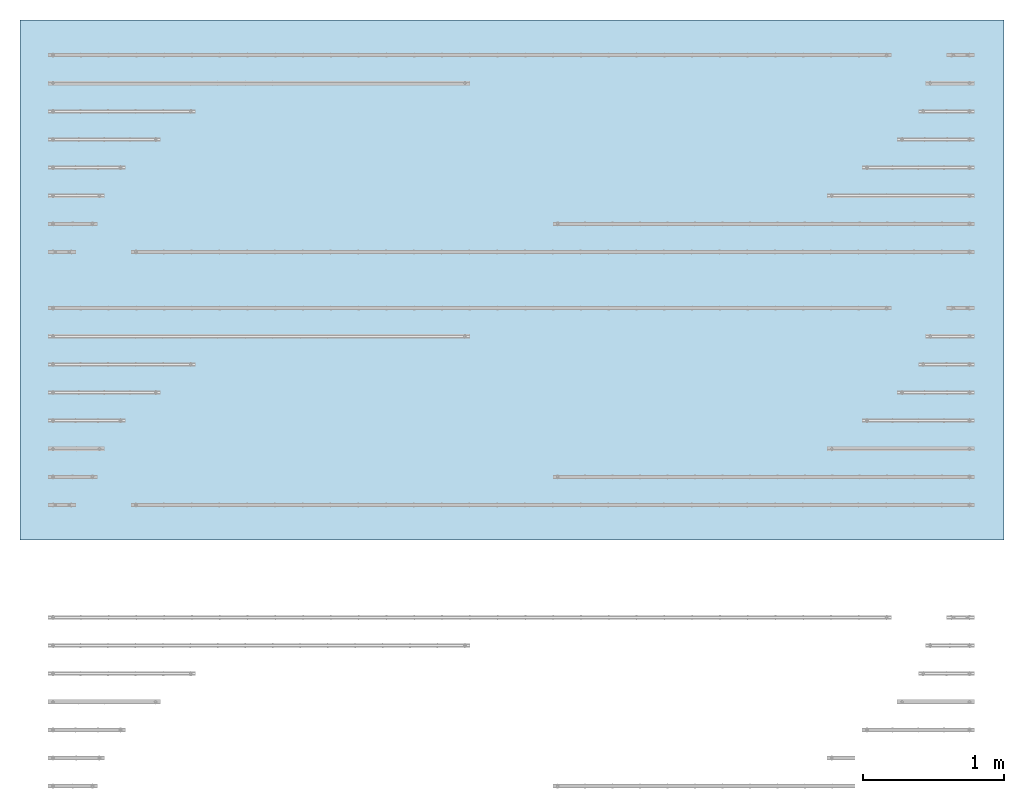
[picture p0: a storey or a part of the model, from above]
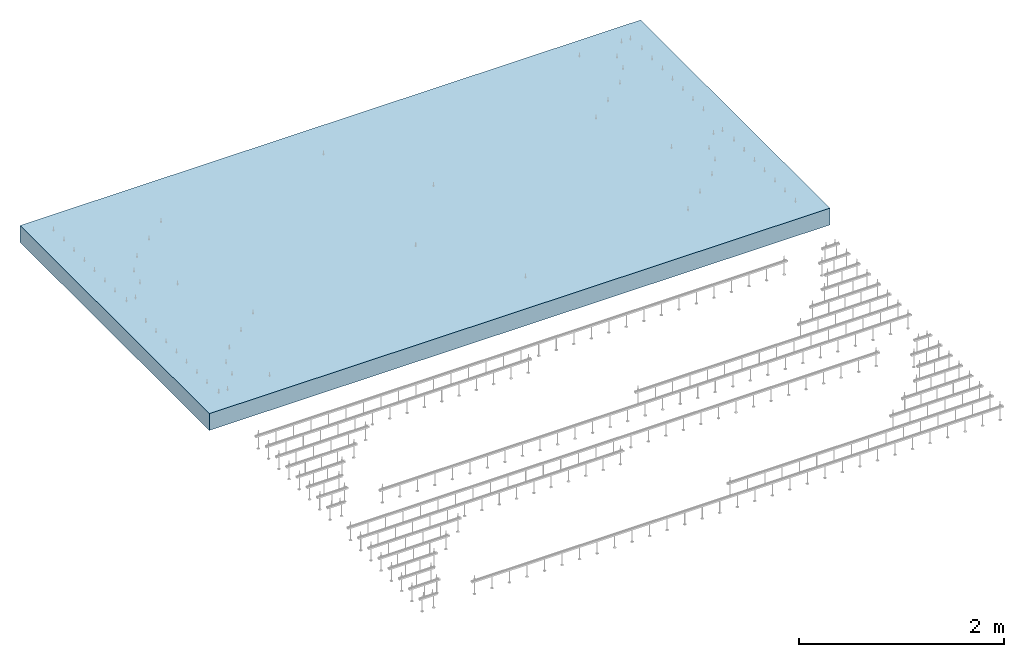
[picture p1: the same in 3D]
Properties of the parts of a building model (IFC2X3)

# File
Description: ViewDefinition [CoordinationView_V2.0]
File name: Projektnummer
Time: 2018-11-02T15:20:55
Written by: The EXPRESS Data Manager Version 5.02.0100.07 : 28 Aug 2013
Made in: 20140606_1530(x64) - Exporter 15.7.0.0 - Alternate UI 15.7.0.0
Comment: STEP Physical File produced by: The EXPRESS Data Manager Version 5.02.0100.07 : 28 Aug 2013 * Module: EDMstepFileFactory/EDMstandAlone * Creation date: Fri Nov 02 15:20:55 2018 * Host: JORNBBLN-012 * Database: C:\Users\DENNIS~1.NEU\AppData\Local\Temp\{C2517105-60E5-48DE-9BF2-83D51E9DFE25}\ifc * Database version: 5507 * Database creation date: Fri Nov 02 15:20:52 2018 * Schema: IFC2X3 * Model: DataRepository.ifc * Model creation date: Fri Nov 02 15:20:52 2018 * Header model: DataRepository.ifc_HeaderModel * Header model creation date: Fri Nov 02 15:20:52 2018 * EDMuser: sdai-user * EDMgroup: sdai-group * License ID and type: 5605 : Permanent license. Expiry date: * EDMstepFileFactory options: 020000

# IfcProject, Projektnummer
LongName: Projektname; Phase: Projektstatus

# IfcSite, Default
RefLatitude: 52, 30, 59, 759999; RefLongitude: 13, 23, 59, 999999; RefElevation: 0 m
Sonstige - Kategorie: Projektinformationen; Kundenname: Bauherr; Projektadresse: Projektadresse; Projektausgabedatum: Projekt Datum; Projektname: Projektname; Projektnummer: Projektnummer; Projektstatus: Projektstatus; Verfasser eMail: E-Mail; Verfasser Firma 1: Firma 1; Verfasser Firma 2: Firma 2; Verfasser PLZ Ort: PLZ Ort; Verfasser Strasse: Strasse; Verfasser Telefax: Telefax; Verfasser Telefon: Telefon

# IfcBuilding
Pset_BuildingCommon - NumberOfStoreys: 1
Sonstige - Kategorie: Projektinformationen; Kundenname: Bauherr; Projektadresse: Projektadresse; Projektausgabedatum: Projekt Datum; Projektname: Projektname; Projektnummer: Projektnummer; Projektstatus: Projektstatus; Verfasser eMail: E-Mail; Verfasser Firma 1: Firma 1; Verfasser Firma 2: Firma 2; Verfasser PLZ Ort: PLZ Ort; Verfasser Strasse: Strasse; Verfasser Telefax: Telefax; Verfasser Telefon: Telefon

# IfcBuildingStorey, Ebene 0
LongName: Ebene 0; Elevation: 0 m
Sonstige(Type) - Kategorie: Ebenen; Familienname: Ebene
ID-Daten(Type) - Typname: Ebene
Grafiken(Type) - Farbe: 16711680; Linienmuster: Verdeckt; Linienstärke: 1; Symbol: Beschriftung Ebene: Beschriftung Ebene; Symbol bei Ende 1 Standard: no; Symbol bei Ende 2 Standard: yes
Abhängigkeiten(Type) - Basishöhe: Projekt-Basispunkt
Abhängigkeiten - Ansicht: 0 m
Abmessungen - Höhe für Berechnung: 0 m
ID-Daten - Tragwerk: no; Gebäudegeschoss: yes; Name: Ebene 0
Sonstige - Familie: Ebene: Ebene; Familie und Typ: Ebene: Ebene; Kategorie: Ebenen; Typ: Ebene: Ebene; Typ-ID: Ebene: Ebene

# IfcFastener: JXA(-PC) L=1050 mm (8)
In: Ebene 0
Type - Material: Steel
Type - Abhängigkeiten(Type) - Vorgabe-Ansicht: 0 m; length: 1.05 m
Type - Allgemein(Type) - min number anchor: 2; tk: 0.002 m
Type - Daten(Type) - min_number_of_T_bolts: 2
Type - ID-Daten(Type) - Beschreibung: Together with the JORDAHL® toothed T-bolts and JORDAHL® accessories, the hot-rolled toothed JORDAHL® anchor channels provide a secure, form-fitting connection along the longitudinal axis of the channel. They can absorb static and dynamic tensile loads, shear loads and longitudinal tension.; Hersteller: JORDAHL®; LOD: 300; Modell: JXA(-PC) W; Typname: JXA(-PC) L=1050 mm; URL: http://www.jordahl-group.com/en/354/products/fastening-technology/toothed-channels-jxa/; Version: 2017-1
Type - Sichtbarkeit(Type) - proof 29-20: W 29-20 JXA JORDAHL®; proof 38-23: W 38-23 JXA JORDAHL®; proof 53-34: W 53-34 JXA JORDAHL®; proof 64-44: W 64-44 JXA JORDAHL®
Type - Sonstige(Type) - Kategorie: Anschluss; Familienname: JXA(-PC) JORDAHL® toothed channels
Type - Text(Type) - delivery date: XX.XX.XXXX; OmniClass Code: 23-13 23 11 11
Pset_ManufacturerTypeInformation - Manufacturer: JORDAHL®
JORDAHL-Liste - JXA-PC: yes; larger T-Bolt size: no; material hot-dip Galvanised steel: no; material stainless steel: yes; b: 0.029 m; b1: 0.013 m; b2: 0.021 m; channel profil: W 29-20 JXA JORDAHL®; delivery date: XX.XX.XXXX; Familie und Typ: JXA(-PC) JORDAHL® toothed channels: JXA(-PC) L=1050 mm; Hersteller: JORDAHL®; length: 1.05 m; Modell: JXA(-PC) W; number of T Bolts: 2; T Bolt length: 0.06 m; T Bolt type: JXD M10
Abhängigkeiten - JXA-PC: yes; larger T-Bolt size: no; channel profil: W 29-20 JXA JORDAHL®; Ebene: Ebene: Ebene 0; Erhebung: 0 m; Warning Overconstraint: no; Assessment Z-21.4-1690: http://downloads.jordahl-group.com/files/approvals/Z-21.4-1690_JORDAHL_anchor_channel_JXA.pdf; Basisbauteil: Ebene : Ebene 0; Website: http://www.jordahl-group.com/en/354/products/fastening-technology/toothed-channels-jxa/
Abmessungen - Fläche: 0.113151 m2; Volumen: 0.000350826 m3
Allgemein - calculate H: 0.146 m; calculate max spacing anchor: 0.2 m; calculate ØbA: 0.006 m; calculate ØD: 0.0145 m; calculate Øk1: 0.018 m; edge distance anchor: 0.035 m; number anchor: 6; ØbA: 0.012 m; ØD: 0.029 m; Øk1: 0.036 m; tD: 0.0025 m
Daten - calculated_number_of_T_bolts: 2; nut_1: no; nut_pair: yes; b1: 0.013 m; b2: 0.021 m; edge distance of the first T Bolt: 0.035 m; k: 0.007 m; l: 0.06 m; max_spacing_length: 0.98 m; max clamping length: 0.04 m; min_spacing_length: 0.05 m; Ød_SharedParameter: 0.01 m; T Bolt group spacing: 0.49 m; T Bolt min length: 0.03 m
ID-Daten - tender text: gezahnte JORDAHL® Ankerschiene JXA ... / ... oder gleichwertig zum Einbetonieren, Material:feuerverzinkt (fv) oder Edelstahl 1.4401; 1.4571; 1.4404 (A4) mit Vollschaumfüllung, nach allgemeiner bauaufsichtlicher Zulassung des DIBt (Zul.Nr. Z-21.4-1690), versehen mit dem RAL Gütezeichen RAL-GZ 658/1 der Gütegemeinschaft Verankerungs- und Bewehrungstechnik e.V. Einzellänge ........ mm, Belastung Fy/Fz und Fx in Schienenrichtung bis ........kN/Befestigungspunkt, bis ......kN nicht ruhende Beanspruchung zulässig, für die justierbare Befestigung von Anschluss- konstruktionen, liefern und entsprechend der Einbau- anleitung des Herstellers an der Schalung befestigen.
Konstruktion - number of T Bolts: 2; min T Bolt edge distance: 0.035 m; T Bolt diameter: 0.01 m; T Bolt length: 0.06 m; T Bolt spacing: 0.98 m; T Bolt type: JXD M10; thickness of attaching part: 0.01 m
Materialien und Oberflächen - material hot-dip Galvanised steel: no; material stainless steel: yes
Modelleigenschaften - b: 0.029 m; d: 0.014 m; f: 0.005 m; f1: 0.003 m; h: 0.02 m; t1: 0.0025 m
Phasen - Phase erstellt: Phase 1
Sonstige - Bauteillistenebene: Ebene: Ebene 0; Kategorie: Anschluss; Familie: JXA(-PC) JORDAHL® toothed channels: JXA(-PC) L=1050 mm; Familie und Typ: JXA(-PC) JORDAHL® toothed channels: JXA(-PC) L=1050 mm; m_nut: 0.008 m; r_Ød: 0.005 m; s_nut: 0.017 m; s_washer: 0.002 m; Typ: JXA(-PC) JORDAHL® toothed channels: JXA(-PC) L=1050 mm; Typ-ID: JXA(-PC) JORDAHL® toothed channels: JXA(-PC) L=1050 mm
Tragwerk - Bewehrungsüberdeckung: Bewehrungsüberdeckung - Einstellungen: Bewehrungsabdeckung 1
Name (JXA(-PC) JORDAHL® toothed channels:JXA(-PC) L=1050 mm:...) | d_washer (m)
383424 | 0.011
385325 | Sonstige - D_washer: 0.02 m
386284 | Sonstige - D_washer: 0.02 m
386292 | Sonstige - D_washer: 0.02 m
417945 | 0.011
417953 | 0.011
417961 | 0.011
417968 | 0.011

# IfcFastener: JXA(-PC) L=200 mm (8)
In: Ebene 0
Type - Material: Steel
Type - Abhängigkeiten(Type) - length: 0.2 m; Vorgabe-Ansicht: 0 m
Type - Allgemein(Type) - min number anchor: 2; tk: 0.002 m
Type - Daten(Type) - min_number_of_T_bolts: 2
Type - ID-Daten(Type) - Beschreibung: Together with the JORDAHL® toothed T-bolts and JORDAHL® accessories, the hot-rolled toothed JORDAHL® anchor channels provide a secure, form-fitting connection along the longitudinal axis of the channel. They can absorb static and dynamic tensile loads, shear loads and longitudinal tension.; Hersteller: JORDAHL®; LOD: 300; Modell: JXA(-PC) W; Typname: JXA(-PC) L=200 mm; URL: http://www.jordahl-group.com/en/354/products/fastening-technology/toothed-channels-jxa/; Version: 2017-1
Type - Sichtbarkeit(Type) - proof 29-20: W 29-20 JXA JORDAHL®; proof 38-23: W 38-23 JXA JORDAHL®; proof 53-34: W 53-34 JXA JORDAHL®; proof 64-44: W 64-44 JXA JORDAHL®
Type - Sonstige(Type) - Kategorie: Anschluss; Familienname: JXA(-PC) JORDAHL® toothed channels
Type - Text(Type) - delivery date: XX.XX.XXXX; OmniClass Code: 23-13 23 11 11
Pset_ManufacturerTypeInformation - Manufacturer: JORDAHL®
JORDAHL-Liste - b: 0.029 m; b1: 0.013 m; b2: 0.021 m; channel profil: W 29-20 JXA JORDAHL®; delivery date: XX.XX.XXXX; Familie und Typ: JXA(-PC) JORDAHL® toothed channels: JXA(-PC) L=200 mm; Hersteller: JORDAHL®; JXA-PC: yes; larger T-Bolt size: no; length: 0.2 m; material hot-dip Galvanised steel: no; material stainless steel: yes; Modell: JXA(-PC) W; number of T Bolts: 2; T Bolt length: 0.06 m; T Bolt type: JXD M10
Abhängigkeiten - JXA-PC: yes; larger T-Bolt size: no; Assessment Z-21.4-1690: http://downloads.jordahl-group.com/files/approvals/Z-21.4-1690_JORDAHL_anchor_channel_JXA.pdf; Basisbauteil: Ebene : Ebene 0; channel profil: W 29-20 JXA JORDAHL®; Ebene: Ebene: Ebene 0; Erhebung: 0 m; Warning Overconstraint: no; Website: http://www.jordahl-group.com/en/354/products/fastening-technology/toothed-channels-jxa/
Abmessungen - Fläche: 0.0309744 m2; Volumen: 0.000105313 m3
Allgemein - calculate H: 0.146 m; calculate max spacing anchor: 0.2 m; calculate ØbA: 0.006 m; calculate ØD: 0.0145 m; calculate Øk1: 0.018 m; edge distance anchor: 0.035 m; number anchor: 2; ØbA: 0.012 m; ØD: 0.029 m; Øk1: 0.036 m; tD: 0.0025 m
Daten - b1: 0.013 m; b2: 0.021 m; calculated_number_of_T_bolts: 2; edge distance of the first T Bolt: 0.05 m; k: 0.007 m; l: 0.06 m; max_spacing_length: 0.13 m; max clamping length: 0.04 m; min_spacing_length: 0.05 m; nut_1: no; nut_pair: yes; Ød_SharedParameter: 0.01 m; T Bolt group spacing: 0.05 m; T Bolt min length: 0.03 m
ID-Daten - tender text: gezahnte JORDAHL® Ankerschiene JXA ... / ... oder gleichwertig zum Einbetonieren, Material:feuerverzinkt (fv) oder Edelstahl 1.4401; 1.4571; 1.4404 (A4) mit Vollschaumfüllung, nach allgemeiner bauaufsichtlicher Zulassung des DIBt (Zul.Nr. Z-21.4-1690), versehen mit dem RAL Gütezeichen RAL-GZ 658/1 der Gütegemeinschaft Verankerungs- und Bewehrungstechnik e.V. Einzellänge ........ mm, Belastung Fy/Fz und Fx in Schienenrichtung bis ........kN/Befestigungspunkt, bis ......kN nicht ruhende Beanspruchung zulässig, für die justierbare Befestigung von Anschluss- konstruktionen, liefern und entsprechend der Einbau- anleitung des Herstellers an der Schalung befestigen.
Konstruktion - min T Bolt edge distance: 0.035 m; number of T Bolts: 2; T Bolt diameter: 0.01 m; T Bolt length: 0.06 m; T Bolt spacing: 0.1 m; T Bolt type: JXD M10; thickness of attaching part: 0.01 m
Materialien und Oberflächen - material hot-dip Galvanised steel: no; material stainless steel: yes
Modelleigenschaften - b: 0.029 m; d: 0.014 m; f: 0.005 m; f1: 0.003 m; h: 0.02 m; t1: 0.0025 m
Phasen - Phase erstellt: Phase 1
Sonstige - Bauteillistenebene: Ebene: Ebene 0; Familie: JXA(-PC) JORDAHL® toothed channels: JXA(-PC) L=200 mm; Familie und Typ: JXA(-PC) JORDAHL® toothed channels: JXA(-PC) L=200 mm; Kategorie: Anschluss; m_nut: 0.008 m; r_Ød: 0.005 m; s_nut: 0.017 m; s_washer: 0.002 m; Typ: JXA(-PC) JORDAHL® toothed channels: JXA(-PC) L=200 mm; Typ-ID: JXA(-PC) JORDAHL® toothed channels: JXA(-PC) L=200 mm
Tragwerk - Bewehrungsüberdeckung: Bewehrungsüberdeckung - Einstellungen: Bewehrungsabdeckung 1
Name (JXA(-PC) JORDAHL® toothed channels:JXA(-PC) L=200 mm:...) | D_washer (m)
382032 | Sonstige - d_washer: 0.011 m
385320 | 0.02
386279 | Sonstige - d_washer: 0.011 m
407395 | 0.02
417940 | 0.02
417948 | 0.02
417956 | 0.02
417971 | Sonstige - d_washer: 0.011 m

# IfcFastener: JXA(-PC) L=3000 mm (8)
In: Ebene 0
Type - Material: Steel
Type - Abhängigkeiten(Type) - Vorgabe-Ansicht: 0 m; length: 3 m
Type - Allgemein(Type) - min number anchor: 2; tk: 0.002 m
Type - Daten(Type) - min_number_of_T_bolts: 2
Type - ID-Daten(Type) - Beschreibung: Together with the JORDAHL® toothed T-bolts and JORDAHL® accessories, the hot-rolled toothed JORDAHL® anchor channels provide a secure, form-fitting connection along the longitudinal axis of the channel. They can absorb static and dynamic tensile loads, shear loads and longitudinal tension.; Hersteller: JORDAHL®; LOD: 300; Modell: JXA(-PC) W; Typname: JXA(-PC) L=3000 mm; URL: http://www.jordahl-group.com/en/354/products/fastening-technology/toothed-channels-jxa/; Version: 2017-1
Type - Sichtbarkeit(Type) - proof 29-20: W 29-20 JXA JORDAHL®; proof 38-23: W 38-23 JXA JORDAHL®; proof 53-34: W 53-34 JXA JORDAHL®; proof 64-44: W 64-44 JXA JORDAHL®
Type - Sonstige(Type) - Kategorie: Anschluss; Familienname: JXA(-PC) JORDAHL® toothed channels
Type - Text(Type) - delivery date: XX.XX.XXXX; OmniClass Code: 23-13 23 11 11
Pset_ManufacturerTypeInformation - Manufacturer: JORDAHL®
JORDAHL-Liste - JXA-PC: yes; larger T-Bolt size: no; material hot-dip Galvanised steel: no; material stainless steel: yes; b: 0.029 m; b1: 0.013 m; b2: 0.021 m; channel profil: W 29-20 JXA JORDAHL®; delivery date: XX.XX.XXXX; Familie und Typ: JXA(-PC) JORDAHL® toothed channels: JXA(-PC) L=3000 mm; Hersteller: JORDAHL®; length: 3 m; Modell: JXA(-PC) W; number of T Bolts: 2; T Bolt length: 0.06 m; T Bolt type: JXD M10
Abhängigkeiten - JXA-PC: yes; larger T-Bolt size: no; channel profil: W 29-20 JXA JORDAHL®; Ebene: Ebene: Ebene 0; Erhebung: 0 m; Warning Overconstraint: no; Assessment Z-21.4-1690: http://downloads.jordahl-group.com/files/approvals/Z-21.4-1690_JORDAHL_anchor_channel_JXA.pdf; Basisbauteil: Ebene : Ebene 0; Website: http://www.jordahl-group.com/en/354/products/fastening-technology/toothed-channels-jxa/
Abmessungen - Fläche: 0.305203 m2; Volumen: 0.00093136 m3
Allgemein - calculate H: 0.146 m; calculate max spacing anchor: 0.2 m; calculate ØbA: 0.006 m; calculate ØD: 0.0145 m; calculate Øk1: 0.018 m; edge distance anchor: 0.035 m; number anchor: 16; ØbA: 0.012 m; ØD: 0.029 m; Øk1: 0.036 m; tD: 0.0025 m
Daten - calculated_number_of_T_bolts: 2; nut_1: no; nut_pair: yes; b1: 0.013 m; b2: 0.021 m; edge distance of the first T Bolt: 0.035 m; k: 0.007 m; l: 0.06 m; max_spacing_length: 2.93 m; max clamping length: 0.04 m; min_spacing_length: 0.05 m; Ød_SharedParameter: 0.01 m; T Bolt group spacing: 1.465 m; T Bolt min length: 0.03 m
ID-Daten - tender text: gezahnte JORDAHL® Ankerschiene JXA ... / ... oder gleichwertig zum Einbetonieren, Material:feuerverzinkt (fv) oder Edelstahl 1.4401; 1.4571; 1.4404 (A4) mit Vollschaumfüllung, nach allgemeiner bauaufsichtlicher Zulassung des DIBt (Zul.Nr. Z-21.4-1690), versehen mit dem RAL Gütezeichen RAL-GZ 658/1 der Gütegemeinschaft Verankerungs- und Bewehrungstechnik e.V. Einzellänge ........ mm, Belastung Fy/Fz und Fx in Schienenrichtung bis ........kN/Befestigungspunkt, bis ......kN nicht ruhende Beanspruchung zulässig, für die justierbare Befestigung von Anschluss- konstruktionen, liefern und entsprechend der Einbau- anleitung des Herstellers an der Schalung befestigen.
Konstruktion - number of T Bolts: 2; min T Bolt edge distance: 0.035 m; T Bolt diameter: 0.01 m; T Bolt length: 0.06 m; T Bolt spacing: 2.93 m; T Bolt type: JXD M10; thickness of attaching part: 0.01 m
Materialien und Oberflächen - material hot-dip Galvanised steel: no; material stainless steel: yes
Modelleigenschaften - b: 0.029 m; d: 0.014 m; f: 0.005 m; f1: 0.003 m; h: 0.02 m; t1: 0.0025 m
Phasen - Phase erstellt: Phase 1
Sonstige - Bauteillistenebene: Ebene: Ebene 0; Kategorie: Anschluss; Familie: JXA(-PC) JORDAHL® toothed channels: JXA(-PC) L=3000 mm; Familie und Typ: JXA(-PC) JORDAHL® toothed channels: JXA(-PC) L=3000 mm; m_nut: 0.008 m; r_Ød: 0.005 m; s_nut: 0.017 m; s_washer: 0.002 m; Typ: JXA(-PC) JORDAHL® toothed channels: JXA(-PC) L=3000 mm; Typ-ID: JXA(-PC) JORDAHL® toothed channels: JXA(-PC) L=3000 mm
Tragwerk - Bewehrungsüberdeckung: Bewehrungsüberdeckung - Einstellungen: Bewehrungsabdeckung 1
Name (JXA(-PC) JORDAHL® toothed channels:JXA(-PC) L=3000 mm:...) | d_washer (m)
383608 | Sonstige - D_washer: 0.02 m
385326 | 0.011
386285 | Sonstige - D_washer: 0.02 m
386293 | 0.011
417946 | Sonstige - D_washer: 0.02 m
417954 | 0.011
417962 | 0.011
417969 | 0.011

# IfcFastener: JXA(-PC) L=350 mm (8)
In: Ebene 0
Type - Material: Steel
Type - Abhängigkeiten(Type) - Vorgabe-Ansicht: 0 m; length: 0.35 m
Type - Allgemein(Type) - min number anchor: 2; tk: 0.002 m
Type - Daten(Type) - min_number_of_T_bolts: 2
Type - ID-Daten(Type) - Beschreibung: Together with the JORDAHL® toothed T-bolts and JORDAHL® accessories, the hot-rolled toothed JORDAHL® anchor channels provide a secure, form-fitting connection along the longitudinal axis of the channel. They can absorb static and dynamic tensile loads, shear loads and longitudinal tension.; Hersteller: JORDAHL®; LOD: 300; Modell: JXA(-PC) W; Typname: JXA(-PC) L=350 mm; URL: http://www.jordahl-group.com/en/354/products/fastening-technology/toothed-channels-jxa/; Version: 2017-1
Type - Sichtbarkeit(Type) - proof 29-20: W 29-20 JXA JORDAHL®; proof 38-23: W 38-23 JXA JORDAHL®; proof 53-34: W 53-34 JXA JORDAHL®; proof 64-44: W 64-44 JXA JORDAHL®
Type - Sonstige(Type) - Kategorie: Anschluss; Familienname: JXA(-PC) JORDAHL® toothed channels
Type - Text(Type) - delivery date: XX.XX.XXXX; OmniClass Code: 23-13 23 11 11
Pset_ManufacturerTypeInformation - Manufacturer: JORDAHL®
JORDAHL-Liste - JXA-PC: yes; larger T-Bolt size: no; material hot-dip Galvanised steel: no; material stainless steel: yes; b: 0.029 m; b1: 0.013 m; b2: 0.021 m; channel profil: W 29-20 JXA JORDAHL®; delivery date: XX.XX.XXXX; Familie und Typ: JXA(-PC) JORDAHL® toothed channels: JXA(-PC) L=350 mm; Hersteller: JORDAHL®; length: 0.35 m; Modell: JXA(-PC) W; number of T Bolts: 2; T Bolt length: 0.06 m; T Bolt type: JXD M10
Abhängigkeiten - JXA-PC: yes; larger T-Bolt size: no; channel profil: W 29-20 JXA JORDAHL®; Ebene: Ebene: Ebene 0; Erhebung: 0 m; Warning Overconstraint: no; Assessment Z-21.4-1690: http://downloads.jordahl-group.com/files/approvals/Z-21.4-1690_JORDAHL_anchor_channel_JXA.pdf; Basisbauteil: Ebene : Ebene 0; Website: http://www.jordahl-group.com/en/354/products/fastening-technology/toothed-channels-jxa/
Abmessungen - Fläche: 0.0467372 m2; Volumen: 0.000154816 m3
Allgemein - calculate H: 0.146 m; calculate max spacing anchor: 0.2 m; calculate ØbA: 0.006 m; calculate ØD: 0.0145 m; calculate Øk1: 0.018 m; edge distance anchor: 0.035 m; number anchor: 3; ØbA: 0.012 m; ØD: 0.029 m; Øk1: 0.036 m; tD: 0.0025 m
Daten - calculated_number_of_T_bolts: 2; nut_1: no; nut_pair: yes; b1: 0.013 m; b2: 0.021 m; edge distance of the first T Bolt: 0.035 m; k: 0.007 m; l: 0.06 m; max_spacing_length: 0.28 m; max clamping length: 0.04 m; min_spacing_length: 0.05 m; Ød_SharedParameter: 0.01 m; T Bolt group spacing: 0.14 m; T Bolt min length: 0.03 m
ID-Daten - tender text: gezahnte JORDAHL® Ankerschiene JXA ... / ... oder gleichwertig zum Einbetonieren, Material:feuerverzinkt (fv) oder Edelstahl 1.4401; 1.4571; 1.4404 (A4) mit Vollschaumfüllung, nach allgemeiner bauaufsichtlicher Zulassung des DIBt (Zul.Nr. Z-21.4-1690), versehen mit dem RAL Gütezeichen RAL-GZ 658/1 der Gütegemeinschaft Verankerungs- und Bewehrungstechnik e.V. Einzellänge ........ mm, Belastung Fy/Fz und Fx in Schienenrichtung bis ........kN/Befestigungspunkt, bis ......kN nicht ruhende Beanspruchung zulässig, für die justierbare Befestigung von Anschluss- konstruktionen, liefern und entsprechend der Einbau- anleitung des Herstellers an der Schalung befestigen.
Konstruktion - number of T Bolts: 2; min T Bolt edge distance: 0.035 m; T Bolt diameter: 0.01 m; T Bolt length: 0.06 m; T Bolt spacing: 0.28 m; T Bolt type: JXD M10; thickness of attaching part: 0.01 m
Materialien und Oberflächen - material hot-dip Galvanised steel: no; material stainless steel: yes
Modelleigenschaften - b: 0.029 m; d: 0.014 m; f: 0.005 m; f1: 0.003 m; h: 0.02 m; t1: 0.0025 m
Phasen - Phase erstellt: Phase 1
Sonstige - Bauteillistenebene: Ebene: Ebene 0; Kategorie: Anschluss; Familie: JXA(-PC) JORDAHL® toothed channels: JXA(-PC) L=350 mm; Familie und Typ: JXA(-PC) JORDAHL® toothed channels: JXA(-PC) L=350 mm; m_nut: 0.008 m; r_Ød: 0.005 m; s_nut: 0.017 m; s_washer: 0.002 m; Typ: JXA(-PC) JORDAHL® toothed channels: JXA(-PC) L=350 mm; Typ-ID: JXA(-PC) JORDAHL® toothed channels: JXA(-PC) L=350 mm
Tragwerk - Bewehrungsüberdeckung: Bewehrungsüberdeckung - Einstellungen: Bewehrungsabdeckung 1
Name (JXA(-PC) JORDAHL® toothed channels:JXA(-PC) L=350 mm:...) | D_washer (m)
382279 | Sonstige - d_washer: 0.011 m
385321 | Sonstige - d_washer: 0.011 m
386280 | 0.02
386288 | 0.02
417941 | 0.02
417949 | 0.02
417957 | 0.02
417964 | Sonstige - d_washer: 0.011 m

# IfcFastener: JXA(-PC) L=400 mm (8)
In: Ebene 0
Type - Material: Steel
Type - Abhängigkeiten(Type) - Vorgabe-Ansicht: 0 m; length: 0.4 m
Type - Allgemein(Type) - min number anchor: 2; tk: 0.002 m
Type - Daten(Type) - min_number_of_T_bolts: 2
Type - ID-Daten(Type) - Beschreibung: Together with the JORDAHL® toothed T-bolts and JORDAHL® accessories, the hot-rolled toothed JORDAHL® anchor channels provide a secure, form-fitting connection along the longitudinal axis of the channel. They can absorb static and dynamic tensile loads, shear loads and longitudinal tension.; Hersteller: JORDAHL®; LOD: 300; Modell: JXA(-PC) W; Typname: JXA(-PC) L=400 mm; URL: http://www.jordahl-group.com/en/354/products/fastening-technology/toothed-channels-jxa/; Version: 2017-1
Type - Sichtbarkeit(Type) - proof 29-20: W 29-20 JXA JORDAHL®; proof 38-23: W 38-23 JXA JORDAHL®; proof 53-34: W 53-34 JXA JORDAHL®; proof 64-44: W 64-44 JXA JORDAHL®
Type - Sonstige(Type) - Kategorie: Anschluss; Familienname: JXA(-PC) JORDAHL® toothed channels
Type - Text(Type) - delivery date: XX.XX.XXXX; OmniClass Code: 23-13 23 11 11
Pset_ManufacturerTypeInformation - Manufacturer: JORDAHL®
JORDAHL-Liste - JXA-PC: yes; larger T-Bolt size: no; material hot-dip Galvanised steel: no; material stainless steel: yes; b: 0.029 m; b1: 0.013 m; b2: 0.021 m; channel profil: W 29-20 JXA JORDAHL®; delivery date: XX.XX.XXXX; Familie und Typ: JXA(-PC) JORDAHL® toothed channels: JXA(-PC) L=400 mm; Hersteller: JORDAHL®; length: 0.4 m; Modell: JXA(-PC) W; number of T Bolts: 2; T Bolt length: 0.06 m; T Bolt type: JXD M10
Abhängigkeiten - JXA-PC: yes; larger T-Bolt size: no; channel profil: W 29-20 JXA JORDAHL®; Ebene: Ebene: Ebene 0; Erhebung: 0 m; Warning Overconstraint: no; Assessment Z-21.4-1690: http://downloads.jordahl-group.com/files/approvals/Z-21.4-1690_JORDAHL_anchor_channel_JXA.pdf; Basisbauteil: Ebene : Ebene 0; Website: http://www.jordahl-group.com/en/354/products/fastening-technology/toothed-channels-jxa/
Abmessungen - Fläche: 0.0505622 m2; Volumen: 0.000164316 m3
Allgemein - number anchor: 3; calculate H: 0.146 m; calculate max spacing anchor: 0.2 m; calculate ØbA: 0.006 m; calculate ØD: 0.0145 m; calculate Øk1: 0.018 m; edge distance anchor: 0.035 m; ØbA: 0.012 m; ØD: 0.029 m; Øk1: 0.036 m; tD: 0.0025 m
Daten - calculated_number_of_T_bolts: 2; nut_1: no; nut_pair: yes; b1: 0.013 m; b2: 0.021 m; edge distance of the first T Bolt: 0.035 m; k: 0.007 m; l: 0.06 m; max_spacing_length: 0.33 m; max clamping length: 0.04 m; min_spacing_length: 0.05 m; Ød_SharedParameter: 0.01 m; T Bolt group spacing: 0.165 m; T Bolt min length: 0.03 m
ID-Daten - tender text: gezahnte JORDAHL® Ankerschiene JXA ... / ... oder gleichwertig zum Einbetonieren, Material:feuerverzinkt (fv) oder Edelstahl 1.4401; 1.4571; 1.4404 (A4) mit Vollschaumfüllung, nach allgemeiner bauaufsichtlicher Zulassung des DIBt (Zul.Nr. Z-21.4-1690), versehen mit dem RAL Gütezeichen RAL-GZ 658/1 der Gütegemeinschaft Verankerungs- und Bewehrungstechnik e.V. Einzellänge ........ mm, Belastung Fy/Fz und Fx in Schienenrichtung bis ........kN/Befestigungspunkt, bis ......kN nicht ruhende Beanspruchung zulässig, für die justierbare Befestigung von Anschluss- konstruktionen, liefern und entsprechend der Einbau- anleitung des Herstellers an der Schalung befestigen.
Konstruktion - number of T Bolts: 2; min T Bolt edge distance: 0.035 m; T Bolt diameter: 0.01 m; T Bolt length: 0.06 m; T Bolt spacing: 0.33 m; T Bolt type: JXD M10; thickness of attaching part: 0.01 m
Materialien und Oberflächen - material hot-dip Galvanised steel: no; material stainless steel: yes
Modelleigenschaften - b: 0.029 m; d: 0.014 m; f: 0.005 m; f1: 0.003 m; h: 0.02 m; t1: 0.0025 m
Phasen - Phase erstellt: Phase 1
Sonstige - Bauteillistenebene: Ebene: Ebene 0; Kategorie: Anschluss; Familie: JXA(-PC) JORDAHL® toothed channels: JXA(-PC) L=400 mm; Familie und Typ: JXA(-PC) JORDAHL® toothed channels: JXA(-PC) L=400 mm; m_nut: 0.008 m; r_Ød: 0.005 m; s_nut: 0.017 m; s_washer: 0.002 m; Typ: JXA(-PC) JORDAHL® toothed channels: JXA(-PC) L=400 mm; Typ-ID: JXA(-PC) JORDAHL® toothed channels: JXA(-PC) L=400 mm
Tragwerk - Bewehrungsüberdeckung: Bewehrungsüberdeckung - Einstellungen: Bewehrungsabdeckung 1
Name (JXA(-PC) JORDAHL® toothed channels:JXA(-PC) L=400 mm:...) | d_washer (m)
382875 | 0.011
385322 | 0.011
386281 | Sonstige - D_washer: 0.02 m
386289 | 0.011
417942 | 0.011
417950 | Sonstige - D_washer: 0.02 m
417958 | 0.011
417965 | Sonstige - D_washer: 0.02 m

# IfcFastener: JXA(-PC) L=550 mm (8)
In: Ebene 0
Type - Material: Steel
Type - Abhängigkeiten(Type) - Vorgabe-Ansicht: 0 m; length: 0.55 m
Type - Allgemein(Type) - min number anchor: 2; tk: 0.002 m
Type - Daten(Type) - min_number_of_T_bolts: 2
Type - ID-Daten(Type) - Beschreibung: Together with the JORDAHL® toothed T-bolts and JORDAHL® accessories, the hot-rolled toothed JORDAHL® anchor channels provide a secure, form-fitting connection along the longitudinal axis of the channel. They can absorb static and dynamic tensile loads, shear loads and longitudinal tension.; Hersteller: JORDAHL®; LOD: 300; Modell: JXA(-PC) W; Typname: JXA(-PC) L=550 mm; URL: http://www.jordahl-group.com/en/354/products/fastening-technology/toothed-channels-jxa/; Version: 2017-1
Type - Sichtbarkeit(Type) - proof 29-20: W 29-20 JXA JORDAHL®; proof 38-23: W 38-23 JXA JORDAHL®; proof 53-34: W 53-34 JXA JORDAHL®; proof 64-44: W 64-44 JXA JORDAHL®
Type - Sonstige(Type) - Kategorie: Anschluss; Familienname: JXA(-PC) JORDAHL® toothed channels
Type - Text(Type) - delivery date: XX.XX.XXXX; OmniClass Code: 23-13 23 11 11
Pset_ManufacturerTypeInformation - Manufacturer: JORDAHL®
JORDAHL-Liste - JXA-PC: yes; larger T-Bolt size: no; material hot-dip Galvanised steel: no; material stainless steel: yes; b: 0.029 m; b1: 0.013 m; b2: 0.021 m; channel profil: W 29-20 JXA JORDAHL®; delivery date: XX.XX.XXXX; Familie und Typ: JXA(-PC) JORDAHL® toothed channels: JXA(-PC) L=550 mm; Hersteller: JORDAHL®; length: 0.55 m; Modell: JXA(-PC) W; number of T Bolts: 2; T Bolt length: 0.06 m; T Bolt type: JXD M10
Abhängigkeiten - JXA-PC: yes; larger T-Bolt size: no; channel profil: W 29-20 JXA JORDAHL®; Ebene: Ebene: Ebene 0; Erhebung: 0 m; Warning Overconstraint: no; Assessment Z-21.4-1690: http://downloads.jordahl-group.com/files/approvals/Z-21.4-1690_JORDAHL_anchor_channel_JXA.pdf; Basisbauteil: Ebene : Ebene 0; Website: http://www.jordahl-group.com/en/354/products/fastening-technology/toothed-channels-jxa/
Abmessungen - Fläche: 0.0663249 m2; Volumen: 0.000213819 m3
Allgemein - calculate H: 0.146 m; calculate max spacing anchor: 0.2 m; calculate ØbA: 0.006 m; calculate ØD: 0.0145 m; calculate Øk1: 0.018 m; edge distance anchor: 0.035 m; number anchor: 4; ØbA: 0.012 m; ØD: 0.029 m; Øk1: 0.036 m; tD: 0.0025 m
Daten - calculated_number_of_T_bolts: 2; nut_1: no; nut_pair: yes; b1: 0.013 m; b2: 0.021 m; edge distance of the first T Bolt: 0.035 m; k: 0.007 m; l: 0.06 m; max_spacing_length: 0.48 m; max clamping length: 0.04 m; min_spacing_length: 0.05 m; Ød_SharedParameter: 0.01 m; T Bolt group spacing: 0.24 m; T Bolt min length: 0.03 m
ID-Daten - tender text: gezahnte JORDAHL® Ankerschiene JXA ... / ... oder gleichwertig zum Einbetonieren, Material:feuerverzinkt (fv) oder Edelstahl 1.4401; 1.4571; 1.4404 (A4) mit Vollschaumfüllung, nach allgemeiner bauaufsichtlicher Zulassung des DIBt (Zul.Nr. Z-21.4-1690), versehen mit dem RAL Gütezeichen RAL-GZ 658/1 der Gütegemeinschaft Verankerungs- und Bewehrungstechnik e.V. Einzellänge ........ mm, Belastung Fy/Fz und Fx in Schienenrichtung bis ........kN/Befestigungspunkt, bis ......kN nicht ruhende Beanspruchung zulässig, für die justierbare Befestigung von Anschluss- konstruktionen, liefern und entsprechend der Einbau- anleitung des Herstellers an der Schalung befestigen.
Konstruktion - number of T Bolts: 2; min T Bolt edge distance: 0.035 m; T Bolt diameter: 0.01 m; T Bolt length: 0.06 m; T Bolt spacing: 0.48 m; T Bolt type: JXD M10; thickness of attaching part: 0.01 m
Materialien und Oberflächen - material hot-dip Galvanised steel: no; material stainless steel: yes
Modelleigenschaften - b: 0.029 m; d: 0.014 m; f: 0.005 m; f1: 0.003 m; h: 0.02 m; t1: 0.0025 m
Phasen - Phase erstellt: Phase 1
Sonstige - Bauteillistenebene: Ebene: Ebene 0; Kategorie: Anschluss; Familie: JXA(-PC) JORDAHL® toothed channels: JXA(-PC) L=550 mm; Familie und Typ: JXA(-PC) JORDAHL® toothed channels: JXA(-PC) L=550 mm; m_nut: 0.008 m; r_Ød: 0.005 m; s_nut: 0.017 m; s_washer: 0.002 m; Typ: JXA(-PC) JORDAHL® toothed channels: JXA(-PC) L=550 mm; Typ-ID: JXA(-PC) JORDAHL® toothed channels: JXA(-PC) L=550 mm
Tragwerk - Bewehrungsüberdeckung: Bewehrungsüberdeckung - Einstellungen: Bewehrungsabdeckung 1
Name (JXA(-PC) JORDAHL® toothed channels:JXA(-PC) L=550 mm:...) | d_washer (m)
383122 | 0.011
385323 | 0.011
386282 | 0.011
386290 | Sonstige - D_washer: 0.02 m
417943 | 0.011
417951 | 0.011
417959 | 0.011
417966 | Sonstige - D_washer: 0.02 m

# IfcFastener: JXA(-PC) L=6000 mm (8)
In: Ebene 0
Type - Material: Steel
Type - Abhängigkeiten(Type) - Vorgabe-Ansicht: 0 m; length: 6 m
Type - Allgemein(Type) - min number anchor: 2; tk: 0.002 m
Type - Daten(Type) - min_number_of_T_bolts: 2
Type - ID-Daten(Type) - Beschreibung: Together with the JORDAHL® toothed T-bolts and JORDAHL® accessories, the hot-rolled toothed JORDAHL® anchor channels provide a secure, form-fitting connection along the longitudinal axis of the channel. They can absorb static and dynamic tensile loads, shear loads and longitudinal tension.; Hersteller: JORDAHL®; LOD: 300; Modell: JXA(-PC) W; Typname: JXA(-PC) L=6000 mm; URL: http://www.jordahl-group.com/en/354/products/fastening-technology/toothed-channels-jxa/; Version: 2017-1
Type - Sichtbarkeit(Type) - proof 29-20: W 29-20 JXA JORDAHL®; proof 38-23: W 38-23 JXA JORDAHL®; proof 53-34: W 53-34 JXA JORDAHL®; proof 64-44: W 64-44 JXA JORDAHL®
Type - Sonstige(Type) - Kategorie: Anschluss; Familienname: JXA(-PC) JORDAHL® toothed channels
Type - Text(Type) - delivery date: XX.XX.XXXX; OmniClass Code: 23-13 23 11 11
Pset_ManufacturerTypeInformation - Manufacturer: JORDAHL®
JORDAHL-Liste - JXA-PC: yes; larger T-Bolt size: no; material hot-dip Galvanised steel: no; material stainless steel: yes; b: 0.029 m; b1: 0.013 m; b2: 0.021 m; channel profil: W 29-20 JXA JORDAHL®; delivery date: XX.XX.XXXX; Familie und Typ: JXA(-PC) JORDAHL® toothed channels: JXA(-PC) L=6000 mm; Hersteller: JORDAHL®; length: 6 m; Modell: JXA(-PC) W; number of T Bolts: 2; T Bolt length: 0.06 m; T Bolt type: JXD M10
Abhängigkeiten - JXA-PC: yes; larger T-Bolt size: no; channel profil: W 29-20 JXA JORDAHL®; Ebene: Ebene: Ebene 0; Erhebung: 0 m; Warning Overconstraint: no; Assessment Z-21.4-1690: http://downloads.jordahl-group.com/files/approvals/Z-21.4-1690_JORDAHL_anchor_channel_JXA.pdf; Basisbauteil: Ebene : Ebene 0; Website: http://www.jordahl-group.com/en/354/products/fastening-technology/toothed-channels-jxa/
Abmessungen - Fläche: 0.59902 m2; Volumen: 0.00181641 m3
Allgemein - calculate H: 0.146 m; calculate max spacing anchor: 0.2 m; calculate ØbA: 0.006 m; calculate ØD: 0.0145 m; calculate Øk1: 0.018 m; edge distance anchor: 0.035 m; number anchor: 31; ØbA: 0.012 m; ØD: 0.029 m; Øk1: 0.036 m; tD: 0.0025 m
Daten - calculated_number_of_T_bolts: 2; nut_1: no; nut_pair: yes; b1: 0.013 m; b2: 0.021 m; edge distance of the first T Bolt: 0.035 m; k: 0.007 m; l: 0.06 m; max_spacing_length: 5.93 m; max clamping length: 0.04 m; min_spacing_length: 0.05 m; Ød_SharedParameter: 0.01 m; T Bolt group spacing: 2.965 m; T Bolt min length: 0.03 m
ID-Daten - tender text: gezahnte JORDAHL® Ankerschiene JXA ... / ... oder gleichwertig zum Einbetonieren, Material:feuerverzinkt (fv) oder Edelstahl 1.4401; 1.4571; 1.4404 (A4) mit Vollschaumfüllung, nach allgemeiner bauaufsichtlicher Zulassung des DIBt (Zul.Nr. Z-21.4-1690), versehen mit dem RAL Gütezeichen RAL-GZ 658/1 der Gütegemeinschaft Verankerungs- und Bewehrungstechnik e.V. Einzellänge ........ mm, Belastung Fy/Fz und Fx in Schienenrichtung bis ........kN/Befestigungspunkt, bis ......kN nicht ruhende Beanspruchung zulässig, für die justierbare Befestigung von Anschluss- konstruktionen, liefern und entsprechend der Einbau- anleitung des Herstellers an der Schalung befestigen.
Konstruktion - number of T Bolts: 2; min T Bolt edge distance: 0.035 m; T Bolt diameter: 0.01 m; T Bolt length: 0.06 m; T Bolt spacing: 5.93 m; T Bolt type: JXD M10; thickness of attaching part: 0.01 m
Materialien und Oberflächen - material hot-dip Galvanised steel: no; material stainless steel: yes
Modelleigenschaften - b: 0.029 m; d: 0.014 m; f: 0.005 m; f1: 0.003 m; h: 0.02 m; t1: 0.0025 m
Phasen - Phase erstellt: Phase 1
Sonstige - Bauteillistenebene: Ebene: Ebene 0; Kategorie: Anschluss; Familie: JXA(-PC) JORDAHL® toothed channels: JXA(-PC) L=6000 mm; Familie und Typ: JXA(-PC) JORDAHL® toothed channels: JXA(-PC) L=6000 mm; m_nut: 0.008 m; r_Ød: 0.005 m; s_nut: 0.017 m; s_washer: 0.002 m; Typ: JXA(-PC) JORDAHL® toothed channels: JXA(-PC) L=6000 mm; Typ-ID: JXA(-PC) JORDAHL® toothed channels: JXA(-PC) L=6000 mm
Tragwerk - Bewehrungsüberdeckung: Bewehrungsüberdeckung - Einstellungen: Bewehrungsabdeckung 1
Name (JXA(-PC) JORDAHL® toothed channels:JXA(-PC) L=6000 mm:...) | d_washer (m)
383844 | Sonstige - D_washer: 0.02 m
385327 | 0.011
386286 | 0.011
386294 | 0.011
417947 | 0.011
417955 | 0.011
417963 | Sonstige - D_washer: 0.02 m
417970 | 0.011

# IfcFastener: JXA(-PC) L=800 mm (8)
In: Ebene 0
Type - Material: Steel
Type - Abhängigkeiten(Type) - Vorgabe-Ansicht: 0 m; length: 0.8 m
Type - Allgemein(Type) - min number anchor: 2; tk: 0.002 m
Type - Daten(Type) - min_number_of_T_bolts: 2
Type - ID-Daten(Type) - Beschreibung: Together with the JORDAHL® toothed T-bolts and JORDAHL® accessories, the hot-rolled toothed JORDAHL® anchor channels provide a secure, form-fitting connection along the longitudinal axis of the channel. They can absorb static and dynamic tensile loads, shear loads and longitudinal tension.; Hersteller: JORDAHL®; LOD: 300; Modell: JXA(-PC) W; Typname: JXA(-PC) L=800 mm; URL: http://www.jordahl-group.com/en/354/products/fastening-technology/toothed-channels-jxa/; Version: 2017-1
Type - Sichtbarkeit(Type) - proof 29-20: W 29-20 JXA JORDAHL®; proof 38-23: W 38-23 JXA JORDAHL®; proof 53-34: W 53-34 JXA JORDAHL®; proof 64-44: W 64-44 JXA JORDAHL®
Type - Sonstige(Type) - Kategorie: Anschluss; Familienname: JXA(-PC) JORDAHL® toothed channels
Type - Text(Type) - delivery date: XX.XX.XXXX; OmniClass Code: 23-13 23 11 11
Pset_ManufacturerTypeInformation - Manufacturer: JORDAHL®
JORDAHL-Liste - JXA-PC: yes; larger T-Bolt size: no; material hot-dip Galvanised steel: no; material stainless steel: yes; b: 0.029 m; b1: 0.013 m; b2: 0.021 m; channel profil: W 29-20 JXA JORDAHL®; delivery date: XX.XX.XXXX; Familie und Typ: JXA(-PC) JORDAHL® toothed channels: JXA(-PC) L=800 mm; Hersteller: JORDAHL®; length: 0.8 m; Modell: JXA(-PC) W; number of T Bolts: 2; T Bolt length: 0.06 m; T Bolt type: JXD M10
Abhängigkeiten - JXA-PC: yes; larger T-Bolt size: no; channel profil: W 29-20 JXA JORDAHL®; Ebene: Ebene: Ebene 0; Erhebung: 0 m; Warning Overconstraint: no; Assessment Z-21.4-1690: http://downloads.jordahl-group.com/files/approvals/Z-21.4-1690_JORDAHL_anchor_channel_JXA.pdf; Basisbauteil: Ebene : Ebene 0; Website: http://www.jordahl-group.com/en/354/products/fastening-technology/toothed-channels-jxa/
Abmessungen - Fläche: 0.0897377 m2; Volumen: 0.000282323 m3
Allgemein - calculate H: 0.146 m; calculate max spacing anchor: 0.2 m; calculate ØbA: 0.006 m; calculate ØD: 0.0145 m; calculate Øk1: 0.018 m; edge distance anchor: 0.035 m; number anchor: 5; ØbA: 0.012 m; ØD: 0.029 m; Øk1: 0.036 m; tD: 0.0025 m
Daten - calculated_number_of_T_bolts: 2; nut_1: no; nut_pair: yes; b1: 0.013 m; b2: 0.021 m; edge distance of the first T Bolt: 0.035 m; k: 0.007 m; l: 0.06 m; max_spacing_length: 0.73 m; max clamping length: 0.04 m; min_spacing_length: 0.05 m; Ød_SharedParameter: 0.01 m; T Bolt group spacing: 0.365 m; T Bolt min length: 0.03 m
ID-Daten - tender text: gezahnte JORDAHL® Ankerschiene JXA ... / ... oder gleichwertig zum Einbetonieren, Material:feuerverzinkt (fv) oder Edelstahl 1.4401; 1.4571; 1.4404 (A4) mit Vollschaumfüllung, nach allgemeiner bauaufsichtlicher Zulassung des DIBt (Zul.Nr. Z-21.4-1690), versehen mit dem RAL Gütezeichen RAL-GZ 658/1 der Gütegemeinschaft Verankerungs- und Bewehrungstechnik e.V. Einzellänge ........ mm, Belastung Fy/Fz und Fx in Schienenrichtung bis ........kN/Befestigungspunkt, bis ......kN nicht ruhende Beanspruchung zulässig, für die justierbare Befestigung von Anschluss- konstruktionen, liefern und entsprechend der Einbau- anleitung des Herstellers an der Schalung befestigen.
Konstruktion - number of T Bolts: 2; min T Bolt edge distance: 0.035 m; T Bolt diameter: 0.01 m; T Bolt length: 0.06 m; T Bolt spacing: 0.73 m; T Bolt type: JXD M10; thickness of attaching part: 0.01 m
Materialien und Oberflächen - material hot-dip Galvanised steel: no; material stainless steel: yes
Modelleigenschaften - b: 0.029 m; d: 0.014 m; f: 0.005 m; f1: 0.003 m; h: 0.02 m; t1: 0.0025 m
Phasen - Phase erstellt: Phase 1
Sonstige - Bauteillistenebene: Ebene: Ebene 0; Kategorie: Anschluss; Familie: JXA(-PC) JORDAHL® toothed channels: JXA(-PC) L=800 mm; Familie und Typ: JXA(-PC) JORDAHL® toothed channels: JXA(-PC) L=800 mm; m_nut: 0.008 m; r_Ød: 0.005 m; s_nut: 0.017 m; s_washer: 0.002 m; Typ: JXA(-PC) JORDAHL® toothed channels: JXA(-PC) L=800 mm; Typ-ID: JXA(-PC) JORDAHL® toothed channels: JXA(-PC) L=800 mm
Tragwerk - Bewehrungsüberdeckung: Bewehrungsüberdeckung - Einstellungen: Bewehrungsabdeckung 1
Name (JXA(-PC) JORDAHL® toothed channels:JXA(-PC) L=800 mm:...) | D_washer (m)
383278 | Sonstige - d_washer: 0.011 m
385324 | 0.02
386283 | 0.02
386291 | 0.02
417944 | 0.02
417952 | Sonstige - d_washer: 0.011 m
417960 | 0.02
417967 | 0.02

# IfcSlab: Geschossdecke:STB 20.0, Geschossdecke:STB 20.0:417873
In: Ebene 0
PredefinedType: FLOOR; Material: Stahlbeton - Ortbeton 0.2 m
Sonstige(Type) - Kategorie: Geschossdecken; Familienname: Geschossdecke
Materialien und Oberflächen(Type) - Tragendes Material: Stahlbeton - Ortbeton
Konstruktion(Type) - Funktion: Innen; Standarddicke: 0.2 m
ID-Daten(Type) - Typname: STB 20.0
Grafiken(Type) - Farbfüllung für groben Maßstab: 0; Füllmuster für groben Maßstab: Standard - Füllung
Analytische Eigenschaften(Type) - Absorptionsgrad: 0.7; Rauigkeit: 3; Thermischer Widerstand (R): 0.191205; Thermisch wirksame Masse: 302220; Wärmeübergangskoeffizient (U): 5.23
Pset_SlabCommon - Reference: Geschossdecke:STB 20.0; IsExternal: no; LoadBearing: no; ThermalTransmittance: 5.23 kg/K/s3; PitchAngle: 0 deg
Abhängigkeiten - Ebene: Ebene: Ebene 0; Für Körper: no; Höhenversatz von Ebene: 0 m; Raumbegrenzung: yes
Abmessungen - Dicke: 0.2 m; Fläche: 25.9 m2; Umfang: 21.4 m; Volumen: 5.18 m3
Phasen - Phase erstellt: Phase 1
Sonstige - Familie: Geschossdecke: STB 20.0; Familie und Typ: Geschossdecke: STB 20.0; Kategorie: Geschossdecken; Typ: Geschossdecke: STB 20.0; Typ-ID: Geschossdecke: STB 20.0
Tragwerk - Berechnungsmodell aktivieren: no; Tragwerk: no
